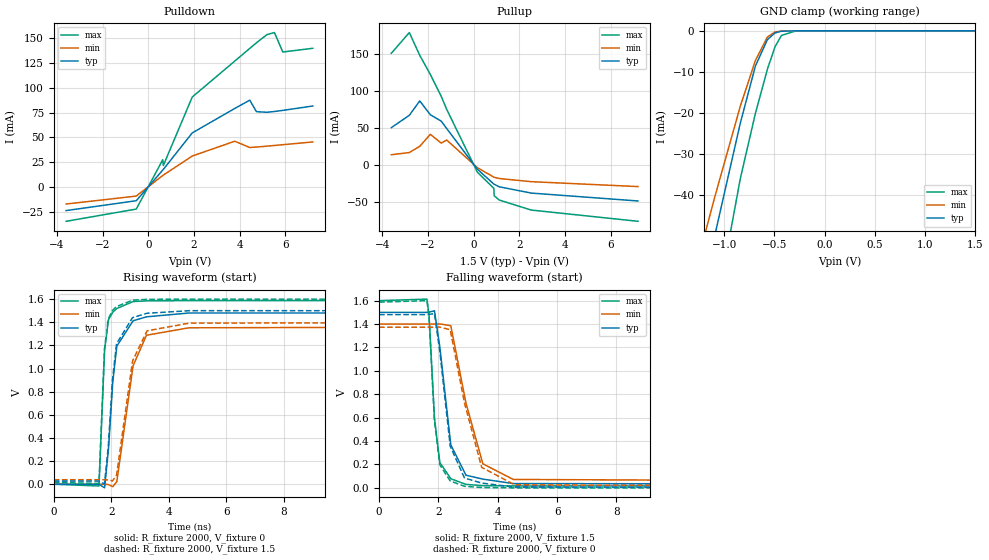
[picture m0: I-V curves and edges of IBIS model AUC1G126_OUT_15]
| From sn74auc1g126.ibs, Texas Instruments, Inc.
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[Model]   AUC1G126_OUT_15
Model_type  3-state
Enable   Active-Low
Vref =   0
Rref =   2000
Cref =   15p
Vmeas =   0.75
| variable   typ   min   max
C_comp   8.46pF   5.30pF   18.84pF
| C_pullup   7.46pF   4.00pF   14.06pF
| C_pulldown   10.55pF   5.75pF   20.45pF
| C_tri-state   8.46pF   5.30pF   18.84pF
[Temperature Range]   40   100   -40
| Ambient temperature   25   85   -40
[Voltage range]   1.5   1.4   1.6
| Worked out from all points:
|   slope of the pulldown table from 0 to 0.225 V, typ, clamps not added: 37 ohm
|   slope of the pullup table from 0 to 0.225 V, typ, clamps not added: 28.1 ohm
|   GND clamp passes 1 mA (typ) near -0.53 V on its own axis
|   rising waveform, R_fixture 2000, V_fixture 0: 20-80 % time 286ps typ, 468ps min, 168ps max; typ from 0 V to 1.48 V
|   falling waveform, R_fixture 2000, V_fixture 1.5: 20-80 % time 407ps typ, 628ps min, 239ps max; typ from 1.5 V to 0.027 V
|   rising waveform, R_fixture 2000, V_fixture 1.5: 20-80 % time 282ps typ, 458ps min, 166ps max; typ from 0.027 V to 1.5 V
|   falling waveform, R_fixture 2000, V_fixture 0: 20-80 % time 404ps typ, 623ps min, 237ps max; typ from 1.48 V to 0 V
[GND Clamp]
| AUC1G126_OUT_15
|   Voltage   I(typ)   I(min)   I(max)
-3.6V     -338.8mA   -286.3mA   -409.7mA
-1.415V   -86.02mA   -70.29mA   -113.7mA
-1.265V   -68.97mA   -56.18mA   -93.1mA
-1.125V   -53.25mA   -43.26mA   -73.93mA
-1.085V   -48.8mA    -39.63mA   -68.47mA
-840mV    -22.47mA   -18.35mA   -35.96mA
-690mV    -8.595mA   -7.233mA   -20.12mA
-570mV    -2.132mA   -1.506mA   -9.318mA
-495mV    -520.9uA   -290.7uA   -3.905mA
-430mV    -104.6uA   -59.7uA    -1.117mA
-285mV    -1.435uA   -1.295uA   -9.372uA
1.5V      350.7pA    6.413nA    352.9pA
[Pulldown]
| AUC1G126_OUT_15
|   Voltage   I(typ)   I(min)   I(max)
-3.6V     -23.47mA   -16.88mA   -34.23mA
-530mV    -13.56mA   -8.913mA   -21.94mA
630mV     17.27mA    11.79mA    27.62mA
655mV     17.88mA    12.18mA    21.8mA
1.92V     54.51mA    31.29mA    90.56mA
3.785V    79.13mA    46.19mA    126.7mA
4.44V     87.4mA     39.87mA    139.4mA
4.73V     75.86mA    40.35mA    145mA
5.195V    75.25mA    41.24mA    153.3mA
5.52V     76.05mA    41.91mA    155.3mA
5.885V    77.14mA    42.68mA    135.8mA
7.2V      81.56mA    45.48mA    139.5mA
[Pullup]
| AUC1G126_OUT_15
|   Voltage   I(typ)   I(min)   I(max)
-3.6V     50.13mA    13.5mA     150.8mA
-2.81V    66.89mA    16.45mA    178.9mA
-2.355V   86.34mA    24.86mA    148.1mA
-1.89V    67.6mA     41.14mA    122.1mA
-1.415V   59mA       29.23mA    92.64mA
-1.175V   48.95mA    33.41mA    74.96mA
170mV     -6.178mA   -4.065mA   -10.23mA
890mV     -26.25mA   -16.87mA   -32.02mA
905mV     -26.53mA   -17.02mA   -41.95mA
1.12V     -29.9mA    -18.7mA    -47.79mA
2.525V    -38.43mA   -23mA      -61.43mA
7.2V      -49.13mA   -29.64mA   -76.65mA
[Ramp]
| AUC1G126_OUT_15
| variable   typ   min   max
dV/dt_r   0.91/2.92E-10   0.84/4.80E-10   0.96/1.69E-10
dV/dt_f   0.89/4.16E-10   0.83/6.46E-10   0.96/2.41E-10
R_load = 2000
[Rising Waveform]
| AUC1G126_OUT_15
R_fixture =   2000
C_fixture =   0
L_fixture =   0
V_fixture =   0
V_fixture_min = 0
V_fixture_max = 0
|   Time   V(typ)   V(min)   V(max)
0s        6.387nV    23.65nV    864.9pV
1.57ns    408.3uV    98.36uV    -15.14mV
1.765ns   -31.31mV   544.1uV    1.16V
1.9ns     305.5mV    -3.52mV    1.422V
2.05ns    886.6mV    -20.47mV   1.488V
2.19ns    1.194V     23.26mV    1.519V
2.755ns   1.413V     1.024V     1.579V
3.22ns    1.447V     1.288V     1.585V
4.69ns    1.48V      1.352V     1.587V
34.99ns   1.481V     1.373V     1.587V
[Falling Waveform]
| AUC1G126_OUT_15
R_fixture =   2000
C_fixture =   0
L_fixture =   0
V_fixture =   1.5
V_fixture_min = 1.4
V_fixture_max = 1.6
|   Time   V(typ)   V(min)   V(max)
0s        1.5V       1.4V       1.6V
1.615ns   1.5V       1.4V       1.613V
1.685ns   1.502V     1.4V       1.482V
1.87ns    1.513V     1.4V       594.8mV
2.05ns    1.204V     1.401V     217.1mV
2.42ns    367.3mV    1.386V     78.04mV
2.93ns    108.3mV    724.6mV    29.57mV
3.5ns     74.69mV    205.6mV    19.07mV
4.525ns   36.68mV    71.85mV    16.43mV
34.99ns   27.18mV    38.78mV    16.4mV
[Rising Waveform]
| AUC1G126_OUT_15
R_fixture =   2000
C_fixture =   0
L_fixture =   0
V_fixture =   1.5
V_fixture_min = 1.4
V_fixture_max = 1.6
|   Time   V(typ)   V(min)   V(max)
0s        27.17mV    38.78mV    16.4mV
1.57ns    27.55mV    38.85mV    7.021mV
1.76ns    2.799mV    39.16mV    1.168V
1.89ns    315.1mV    36.83mV    1.429V
2.04ns    904.7mV    28.95mV    1.502V
2.18ns    1.215V     77.82mV    1.536V
2.735ns   1.44V      1.065V     1.591V
3.24ns    1.478V     1.326V     1.598V
4.715ns   1.5V       1.393V     1.6V
34.99ns   1.5V       1.4V       1.6V
[Falling Waveform]
| AUC1G126_OUT_15
R_fixture =   2000
C_fixture =   0
L_fixture =   0
V_fixture =   0
V_fixture_min = 0
V_fixture_max = 0
|   Time   V(typ)   V(min)   V(max)
0s        1.481V     1.373V     1.587V
1.615ns   1.481V     1.373V     1.6V
1.685ns   1.482V     1.373V     1.464V
1.87ns    1.49V      1.373V     568.7mV
2.05ns    1.165V     1.374V     196.8mV
2.4ns     356.4mV    1.351V     58.96mV
2.88ns    84.13mV    726.3mV    13.4mV
3.46ns    40.77mV    175.3mV    2.819mV
4.57ns    6.384mV    26mV       -1.042uV
34.99ns   2.898uV    -1.178uV   129.9nV
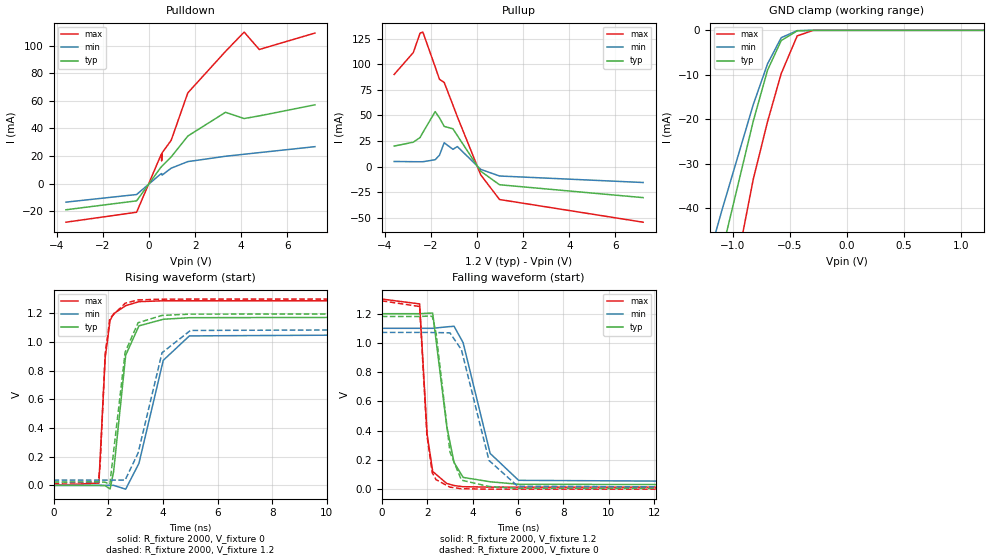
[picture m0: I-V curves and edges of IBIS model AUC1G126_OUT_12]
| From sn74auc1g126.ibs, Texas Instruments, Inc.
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[Model]   AUC1G126_OUT_12
Model_type  3-state
Enable   Active-Low
Vref =   0
Rref =   2000
Cref =   15p
Vmeas =   0.6
| variable   typ   min   max
C_comp   9.33pF   5.50pF   19.02pF
| C_pullup   10.79pF   3.24pF   21.90pF
| C_pulldown   11.71pF   5.76pF   22.03pF
| C_tri-state   9.33pF   5.50pF   19.02pF
[Temperature Range]   40   100   -40
| Ambient temperature   25   85   -40
[Voltage range]   1.2   1.1   1.3
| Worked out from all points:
|   slope of the pulldown table from 0 to 0.18 V, typ, clamps not added: 42.3 ohm
|   slope of the pullup table from 0 to 0.18 V, typ, clamps not added: 34.6 ohm
|   GND clamp passes 1 mA (typ) near -0.53 V on its own axis
|   rising waveform, R_fixture 2000, V_fixture 0: 20-80 % time 404ps typ, 785ps min, 214ps max; typ from 0 V to 1.18 V
|   falling waveform, R_fixture 2000, V_fixture 1.2: 20-80 % time 558ps typ, 1ns min, 301ps max; typ from 1.2 V to 0.024 V
|   rising waveform, R_fixture 2000, V_fixture 1.2: 20-80 % time 395ps typ, 768ps min, 210ps max; typ from 0.024 V to 1.2 V
|   falling waveform, R_fixture 2000, V_fixture 0: 20-80 % time 551ps typ, 1.01ns min, 298ps max; typ from 1.18 V to 0 V
[GND Clamp]
| AUC1G126_OUT_12
|   Voltage   I(typ)   I(min)   I(max)
-3.6V     -338.8mA   -286.3mA   -409.7mA
-1.445V   -89.45mA   -73.14mA   -117.7mA
-1.32V    -75.2mA    -61.33mA   -100.6mA
-1.28V    -70.67mA   -57.58mA   -95.15mA
-1.13V    -53.81mA   -43.72mA   -74.62mA
-1.095V   -49.91mA   -40.54mA   -69.84mA
-820mV    -20.45mA   -16.73mA   -33.53mA
-695mV    -8.981mA   -7.553mA   -20.59mA
-575mV    -2.299mA   -1.652mA   -9.733mA
-435mV    -119.5uA   -67.45uA   -1.256mA
-295mV    -1.95uA    -1.721uA   -13.96uA
1.2V      281.9pA    6.337nA    254pA
[Pulldown]
| AUC1G126_OUT_12
|   Voltage   I(typ)   I(min)   I(max)
-3.6V     -18.86mA   -13.33mA   -27.86mA
-535mV    -12.4mA    -7.815mA   -20.65mA
495mV     11.41mA    6.857mA    19.85mA
545mV     12.35mA    7.329mA    21.54mA
550mV     12.44mA    7.375mA    16.48mA
570mV     12.79mA    6.265mA    22.32mA
965mV     19.42mA    11.26mA    31.49mA
1.685V    34.52mA    16.01mA    65.78mA
3.32V     51.72mA    19.88mA    95.8mA
4.13V     47.2mA     21.35mA    109.8mA
4.785V    49.12mA    22.52mA    97.19mA
7.2V      57.15mA    26.83mA    109.1mA
[Pullup]
| AUC1G126_OUT_12
|   Voltage   I(typ)   I(min)   I(max)
-3.6V     20.02mA    4.99mA     89.94mA
-2.77V    23.81mA    4.762mA    111.3mA
-2.475V   28.39mA    4.727mA    130.3mA
-2.355V   33.26mA    4.746mA    131.3mA
-1.82V    53.68mA    6.71mA     97.32mA
-1.635V   47.58mA    11.11mA    85.27mA
-1.43V    39.24mA    23.25mA    82.18mA
-1.05V    36.9mA     16.86mA    60mA
-860mV    30.31mA    19.57mA    48.76mA
155mV     -4.519mA   -2.712mA   -8.028mA
970mV     -17.73mA   -9.185mA   -32.13mA
7.2V      -30.3mA    -15.54mA   -54.28mA
[Ramp]
| AUC1G126_OUT_12
| variable   typ   min   max
dV/dt_r   0.73/4.16E-10   0.66/8.24E-10   0.78/2.19E-10
dV/dt_f   0.71/5.66E-10   0.65/1.04E-09   0.77/3.10E-10
R_load = 2000
[Rising Waveform]
| AUC1G126_OUT_12
R_fixture =   2000
C_fixture =   0
L_fixture =   0
V_fixture =   0
V_fixture_min = 0
V_fixture_max = 0
|   Time   V(typ)   V(min)   V(max)
0s        5.968nV    25.09nV    694.9pV
1.66ns    165.9uV    -17.06uV   16.41mV
1.89ns    -2.215mV   71.24uV    890mV
2.07ns    -25.13mV   531uV      1.152V
2.2ns     98.09mV    228uV      1.198V
2.64ns    908mV      -26.28mV   1.254V
3.125ns   1.113V     153.7mV    1.282V
4.015ns   1.159V     872.5mV    1.288V
4.97ns    1.17V      1.043V     1.288V
34.99ns   1.181V     1.072V     1.288V
[Falling Waveform]
| AUC1G126_OUT_12
R_fixture =   2000
C_fixture =   0
L_fixture =   0
V_fixture =   1.2
V_fixture_min = 1.1
V_fixture_max = 1.3
|   Time   V(typ)   V(min)   V(max)
0s        1.2V       1.1V       1.3V
1.67ns    1.2V       1.1V       1.267V
2ns       1.203V     1.1V       375.2mV
2.245ns   1.204V     1.1V       121mV
2.865ns   429.3mV    1.11V      38.87mV
3.185ns   182.4mV    1.114V     24.75mV
3.585ns   80.39mV    1.002V     16.8mV
4.775ns   50.46mV    244.5mV    13.91mV
6.03ns    33.41mV    60.19mV    13.8mV
34.99ns   23.98mV    36.64mV    13.86mV
[Rising Waveform]
| AUC1G126_OUT_12
R_fixture =   2000
C_fixture =   0
L_fixture =   0
V_fixture =   1.2
V_fixture_min = 1.1
V_fixture_max = 1.3
|   Time   V(typ)   V(min)   V(max)
0s        23.98mV    36.64mV    13.86mV
1.64ns    24.07mV    36.64mV    25.16mV
1.705ns   24.14mV    36.64mV    141.7mV
1.89ns    22.39mV    36.69mV    918.6mV
2.06ns    8.019mV    36.91mV    1.166V
2.62ns    929.9mV    37.23mV    1.271V
3.095ns   1.135V     226.5mV    1.294V
3.97ns    1.186V     925.7mV    1.299V
5.01ns    1.195V     1.081V     1.3V
34.99ns   1.2V       1.1V       1.3V
[Falling Waveform]
| AUC1G126_OUT_12
R_fixture =   2000
C_fixture =   0
L_fixture =   0
V_fixture =   0
V_fixture_min = 0
V_fixture_max = 0
|   Time   V(typ)   V(min)   V(max)
0s        1.181V     1.072V     1.288V
1.67ns    1.181V     1.072V     1.249V
1.99ns    1.183V     1.072V     369.2mV
2.225ns   1.182V     1.071V     112.4mV
2.395ns   1.067V     1.071V     64.57mV
3.005ns   253.4mV    1.069V     13.81mV
3.51ns    61.57mV    953.7mV    2.953mV
4.725ns   18.11mV    196.2mV    -73.62uV
5.99ns    5.35mV     20.01mV    -69.82uV
34.99ns   3.332uV    -1.482uV   50.98nV
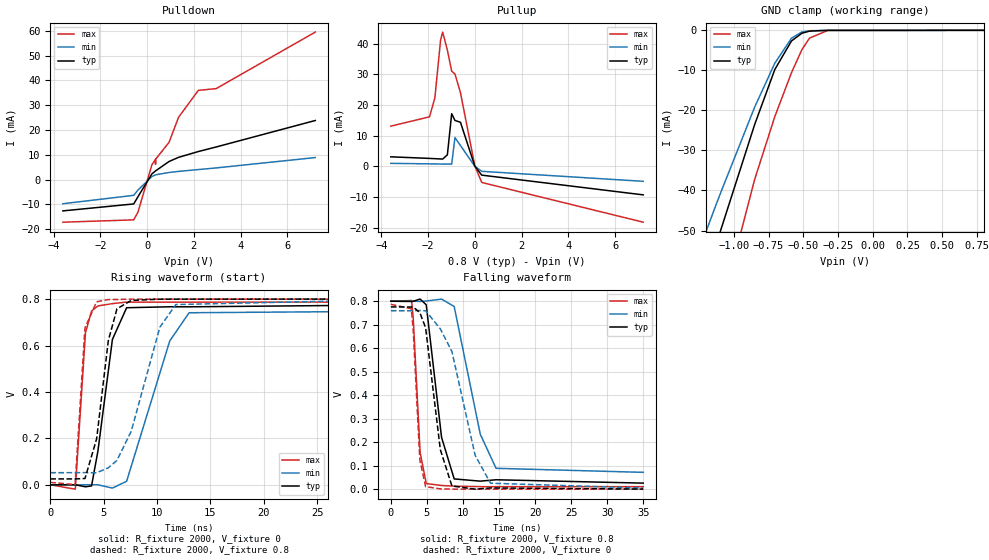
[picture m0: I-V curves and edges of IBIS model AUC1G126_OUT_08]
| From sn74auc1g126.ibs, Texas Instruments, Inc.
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[Model]   AUC1G126_OUT_08
Model_type  3-state
Enable   Active-Low
Vref =   0
Rref =   2000
Cref =   15p
Vmeas =   0.4
| variable   typ   min   max
C_comp   5.5pF   NA   NA
| C_pullup   15.56pF   4.46pF   39.07pF
| C_pulldown   13.26pF   5.97pF   27.74pF
| C_tri-state   10.24pF   5.81pF   19.15pF
[Temperature Range]   40   100   -40
| Ambient temperature   25   85   -40
[Voltage range]   0.8   0.8   0.8
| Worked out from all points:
|   slope of the pulldown table from 0 to 0.12 V, typ, clamps not added: 77 ohm
|   slope of the pullup table from 0 to 0.12 V, typ, clamps not added: 73.2 ohm
|   GND clamp passes 1 mA (typ) near -0.53 V on its own axis
|   rising waveform, R_fixture 2000, V_fixture 0: 20-80 % time 1.31ns typ, 2.69ns min, 612ps max; typ from 0 V to 0.776 V
|   falling waveform, R_fixture 2000, V_fixture 0.8: 20-80 % time 1.73ns typ, 2.65ns min, 795ps max; typ from 0.8 V to 0.025 V
|   rising waveform, R_fixture 2000, V_fixture 0.8: 20-80 % time 1.23ns typ, 2.68ns min, 578ps max; typ from 0.025 V to 0.8 V
|   falling waveform, R_fixture 2000, V_fixture 0: 20-80 % time 1.76ns typ, 3.44ns min, 764ps max; typ from 0.776 V to 0 V
[GND Clamp]
| AUC1G126_OUT_08
|   Voltage   I(typ)   I(min)   I(max)
-3.6V     -338.8mA   -286.3mA   -409.7mA
-1.46V    -91.16mA   -74.57mA   -119.8mA
-1.315V   -74.64mA   -60.86mA   -99.95mA
-1.145V   -55.48mA   -45.09mA   -76.67mA
-1.105V   -51.02mA   -41.44mA   -71.2mA
-850mV    -23.5mA    -19.16mA   -37.2mA
-705mV    -9.778mA   -8.207mA   -21.54mA
-585mV    -2.658mA   -1.97mA    -10.58mA
-510mV    -720.3uA   -415.7uA   -4.835mA
-455mV    -200.7uA   -109.9uA   -1.937mA
-325mV    -4.908uA   -3.982uA   -43.96uA
800mV     202.9pA    373.5pA    160.8pA
[Pulldown]
| AUC1G126_OUT_08
|   Voltage   I(typ)   I(min)   I(max)
-3.6V     -12.63mA   -9.733mA   -17.19mA
-570mV    -9.824mA   -6.355mA   -16.25mA
-390mV    -6.95mA    -4.235mA   -13.17mA
210mV     2.329mA    1.254mA    6.027mA
360mV     3.461mA    1.896mA    8.13mA
365mV     3.499mA    1.915mA    6.143mA
370mV     3.537mA    1.934mA    8.258mA
940mV     7.294mA    2.859mA    14.99mA
1.35V     8.984mA    3.307mA    25.17mA
2.195V    11.32mA    4.051mA    36mA
2.96V     13.17mA    4.715mA    36.72mA
7.2V      23.85mA    8.893mA    59.53mA
[Pullup]
| AUC1G126_OUT_08
|   Voltage   I(typ)   I(min)   I(max)
-3.6V     3.125mA    996.6uA    13.12mA
-1.945V   2.606mA    831.4uA    16.15mA
-1.715V   2.521mA    806.3uA    22.32mA
-1.47V    2.426mA    778.1uA    41.17mA
-1.38V    2.394mA    767.1uA    43.77mA
-1.18V    3.77mA     740.3uA    37.88mA
-995mV    17.17mA    768.8uA    31.03mA
-855mV    14.97mA    9.412mA    30.1mA
-620mV    14.38mA    6.802mA    24.04mA
-5mV      83.77uA    50.86uA    153.9uA
290mV     -2.844mA   -1.602mA   -5.233mA
7.2V      -9.277mA   -4.859mA   -18.18mA
[Ramp]
| AUC1G126_OUT_08
| variable   typ   min   max
dV/dt_r   0.48/1.36E-09   0.46/2.84E-09   0.49/6.22E-10
dV/dt_f   0.47/1.79E-09   0.45/2.84E-09   0.48/8.25E-10
R_load = 2000
[Rising Waveform]
| AUC1G126_OUT_08
R_fixture =   2000
C_fixture =   0
L_fixture =   0
V_fixture =   0
V_fixture_min = 0
V_fixture_max = 0
|   Time   V(typ)   V(min)   V(max)
0s        7.306nV    40.95nV    518.4pV
2.345ns   48.32uV    -28.34uV   -18.75mV
3.295ns   -8.52mV    145.9uV    654.6mV
3.865ns   -4.616mV   627.3uV    748.4mV
4.46ns    144.9mV    33.18uV    770.3mV
5.82ns    626.3mV    -14.02mV   780.4mV
7.15ns    762.7mV    15.35mV    786.9mV
11.19ns   766.8mV    619.9mV    786.8mV
13ns      766.6mV    741.1mV    786.8mV
34.99ns   775.8mV    748.4mV    786.9mV
[Falling Waveform]
| AUC1G126_OUT_08
R_fixture =   2000
C_fixture =   0
L_fixture =   0
V_fixture =   0.8
V_fixture_min = 0.8
V_fixture_max = 0.8
|   Time   V(typ)   V(min)   V(max)
0s        800mV      800mV      800mV
2.88ns    799mV      800mV      803.2mV
3.11ns    799.8mV    799.9mV    726.2mV
4.06ns    809.2mV    799.1mV    157.1mV
4.91ns    784.9mV    800.8mV    23.7mV
7.035ns   220.4mV    809mV      15.39mV
8.785ns   43.39mV    777.6mV    12.59mV
12.4ns    33.87mV    233.9mV    10.59mV
14.59ns   39.81mV    88.46mV    10.6mV
34.99ns   25.48mV    71.34mV    10.6mV
[Rising Waveform]
| AUC1G126_OUT_08
R_fixture =   2000
C_fixture =   0
L_fixture =   0
V_fixture =   0.8
V_fixture_min = 0.8
V_fixture_max = 0.8
|   Time   V(typ)   V(min)   V(max)
0s        25.46mV    52.25mV    10.6mV
2.325ns   25.43mV    52.29mV    929.7uV
3.25ns    27.19mV    52.47mV    675.9mV
4.34ns    197.8mV    51.73mV    788.2mV
5.435ns   620.8mV    73.44mV    797.9mV
6.245ns   758.1mV    105.1mV    798.2mV
7.58ns    794mV      230.7mV    800mV
10.26ns   799.5mV    678.7mV    799.9mV
11.76ns   799.6mV    776.4mV    799.9mV
34.99ns   800mV      799.9mV    800mV
[Falling Waveform]
| AUC1G126_OUT_08
R_fixture =   2000
C_fixture =   0
L_fixture =   0
V_fixture =   0
V_fixture_min = 0
V_fixture_max = 0
|   Time   V(typ)   V(min)   V(max)
0s        775.8mV    759.7mV    786.9mV
2.84ns    775.3mV    759.6mV    768.2mV
3.09ns    775.9mV    759.5mV    684.9mV
4.025ns   751.4mV    760.4mV    123.6mV
4.825ns   686.8mV    759.4mV    10.49mV
6.865ns   167.9mV    682.4mV    941.5uV
8.47ns    13.4mV     585.9mV    -764.8nV
11.69ns   -250.8uV   143.8mV    -4.752uV
13.82ns   5.025mV    25.18mV    -442.8nV
34.99ns   5.828uV    4.462mV    17.55nV
